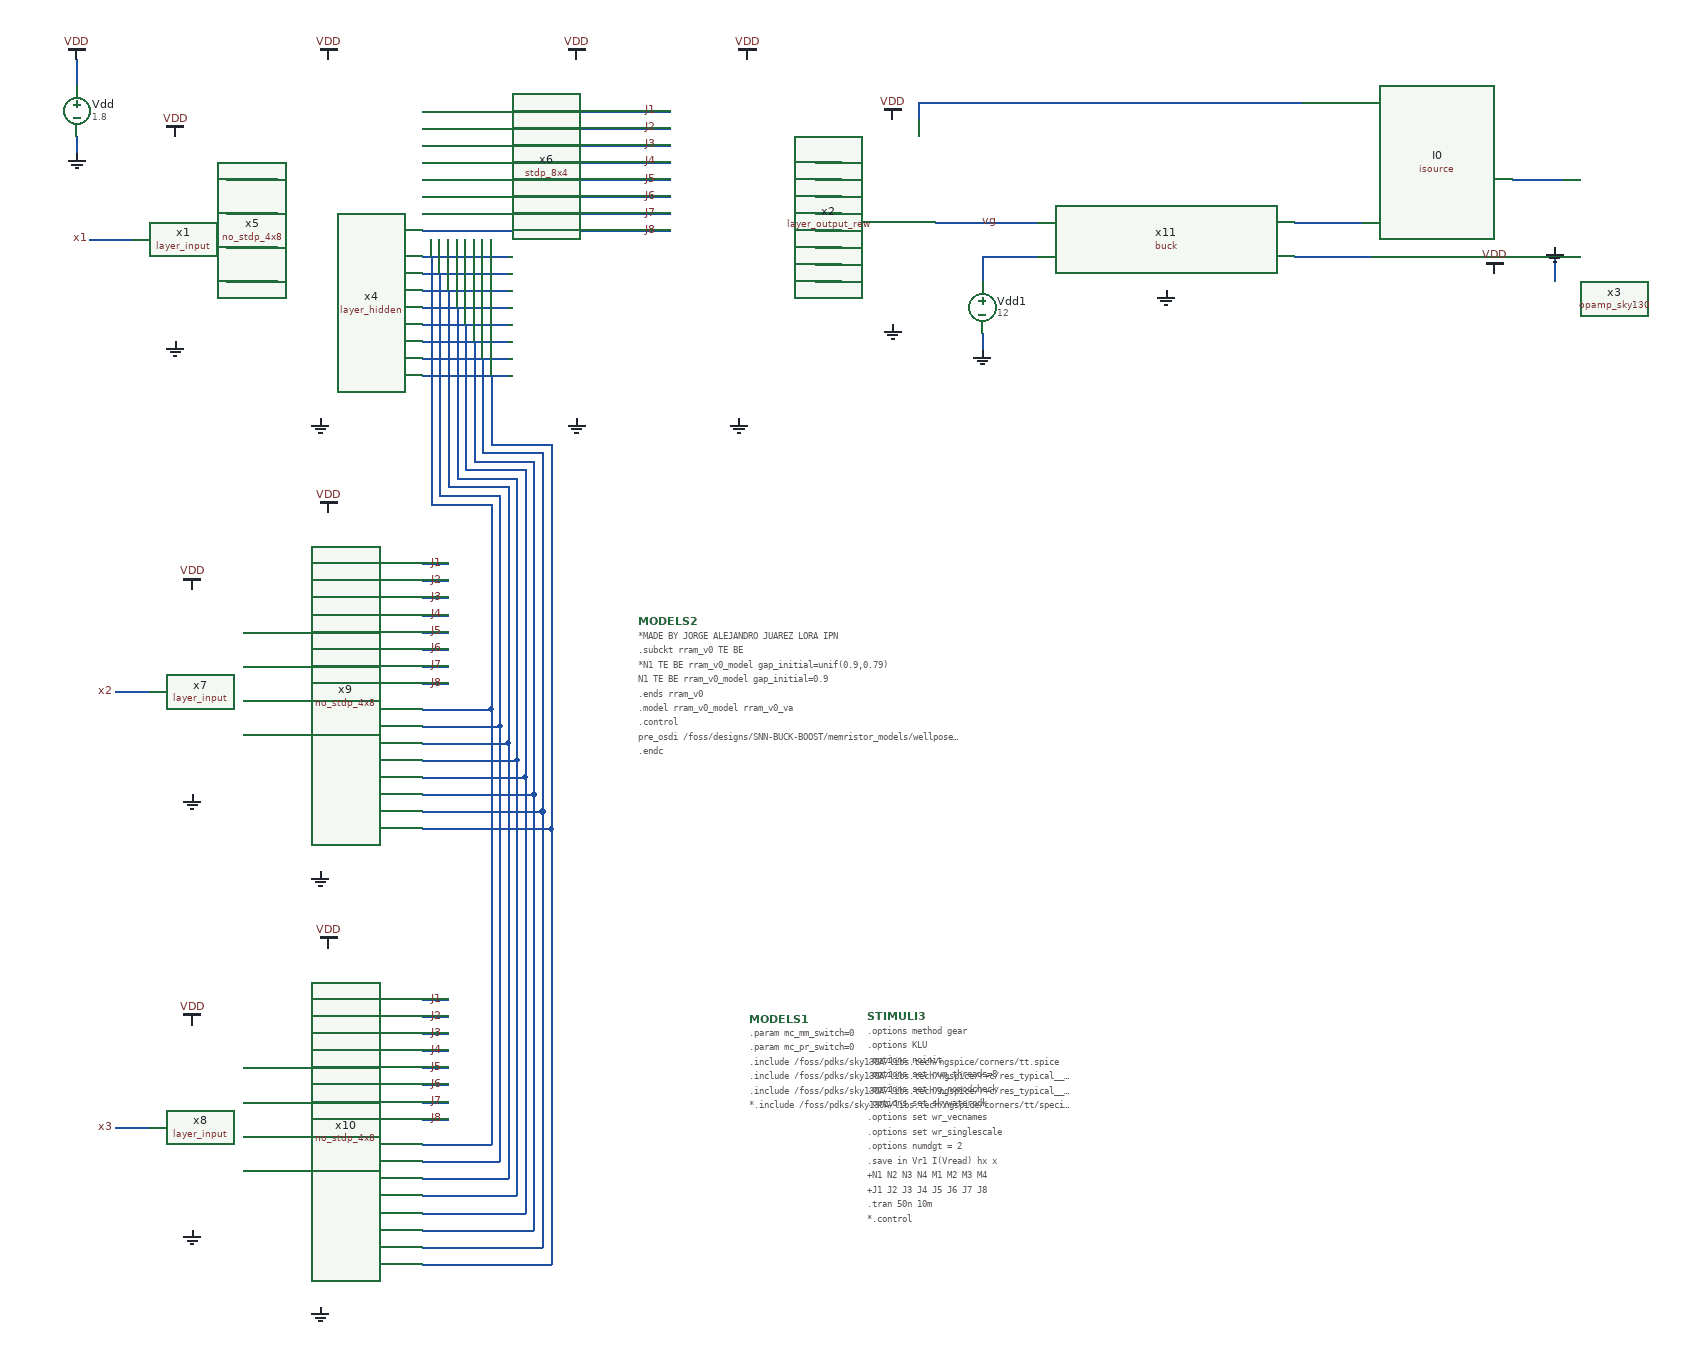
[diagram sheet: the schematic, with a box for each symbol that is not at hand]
v {xschem version=3.4.8RC file_version=1.3}
G {}
K {}
V {}
S {}
F {}
E {}
N 145 -560 145 -530 {
lab=VDD}
N 145 -470 145 -450 {
lab=GND}
N 320 -420 380 -420 {
lab=N1}
N 320 -380 380 -380 {
lab=N2}
N 320 -340 380 -340 {
lab=N3}
N 320 -300 380 -300 {
lab=N4}
N 550 -310 580 -310 {
lab=#net1}
N 550 -330 580 -330 {
lab=#net2}
N 620 -500 840 -500 {
lab=J1}
N 620 -480 840 -480 {
lab=J2}
N 620 -460 840 -460 {
lab=J3}
N 620 -440 840 -440 {
lab=J4}
N 620 -420 840 -420 {
lab=J5}
N 620 -400 840 -400 {
lab=J6}
N 620 -380 840 -380 {
lab=J7}
N 620 -360 840 -360 {
lab=J8}
N 1010 -440 1040 -440 {
lab=M1}
N 1010 -420 1040 -420 {
lab=#net3}
N 1010 -400 1040 -400 {
lab=M2}
N 1010 -380 1040 -380 {
lab=#net4}
N 1010 -360 1040 -360 {
lab=M3}
N 1010 -340 1040 -340 {
lab=#net5}
N 1010 -320 1040 -320 {
lab=M4}
N 1010 -300 1040 -300 {
lab=#net6}
N 1825 -420 1885 -420 {
lab=#net7}
N 1875 -340 1875 -300 {
lab=GND}
N 160 -350 210 -350 {lab=x1}
N 1130 -510 1130 -490 {lab=#net8}
N 1130 -510 1580 -510 {lab=#net8}
N 190 180 230 180 {lab=x2}
N 190 690 230 690 {lab=x3}
N 550 30 580 30 {lab=J1}
N 550 50 580 50 {lab=J2}
N 550 70 580 70 {lab=J3}
N 550 90 580 90 {lab=J4}
N 550 110 580 110 {lab=J5}
N 550 130 580 130 {lab=J6}
N 550 150 580 150 {lab=J7}
N 550 170 580 170 {lab=J8}
N 550 200 630 200 {lab=#net2}
N 630 -40 630 200 {lab=#net2}
N 560 -40 630 -40 {lab=#net2}
N 560 -330 560 -40 {lab=#net2}
N 550 220 640 220 {lab=#net1}
N 640 -50 640 220 {lab=#net1}
N 570 -50 640 -50 {lab=#net1}
N 570 -310 570 -50 {lab=#net1}
N 550 -500 620 -500 {lab=J1}
N 550 -480 620 -480 {lab=J2}
N 550 -460 620 -460 {lab=J3}
N 550 -440 620 -440 {lab=J4}
N 550 -420 620 -420 {lab=J5}
N 550 -400 620 -400 {lab=J6}
N 550 -380 620 -380 {lab=J7}
N 550 -360 620 -360 {lab=J8}
N 580 -330 650 -330 {lab=#net2}
N 580 -310 650 -310 {lab=#net1}
N 550 240 650 240 {lab=#net9}
N 650 -60 650 240 {lab=#net9}
N 580 -60 650 -60 {lab=#net9}
N 550 -290 650 -290 {lab=#net9}
N 550 -270 650 -270 {lab=#net10}
N 550 -250 650 -250 {lab=#net11}
N 550 -230 650 -230 {lab=#net12}
N 550 -210 650 -210 {lab=#net13}
N 550 -190 650 -190 {lab=#net14}
N 580 -290 580 -60 {lab=#net9}
N 550 260 660 260 {lab=#net10}
N 660 -70 660 260 {lab=#net10}
N 590 -70 660 -70 {lab=#net10}
N 590 -270 590 -70 {lab=#net10}
N 550 280 670 280 {lab=#net11}
N 670 -80 670 280 {lab=#net11}
N 600 -80 670 -80 {lab=#net11}
N 600 -250 600 -80 {lab=#net11}
N 550 300 680 300 {lab=#net12}
N 680 -90 680 300 {lab=#net12}
N 610 -90 680 -90 {lab=#net12}
N 610 -230 610 -90 {lab=#net12}
N 550 320 690 320 {lab=#net13}
N 690 -100 690 320 {lab=#net13}
N 620 -100 690 -100 {lab=#net13}
N 620 -210 620 -100 {lab=#net13}
N 550 340 700 340 {lab=#net14}
N 700 -110 700 340 {lab=#net14}
N 630 -110 700 -110 {lab=#net14}
N 630 -190 630 -110 {lab=#net14}
N 550 540 580 540 {lab=J1}
N 550 560 580 560 {lab=J2}
N 550 580 580 580 {lab=J3}
N 550 600 580 600 {lab=J4}
N 550 620 580 620 {lab=J5}
N 550 640 580 640 {lab=J6}
N 550 660 580 660 {lab=J7}
N 550 680 580 680 {lab=J8}
N 630 200 630 710 {lab=#net2}
N 550 710 630 710 {lab=#net2}
N 640 220 640 730 {lab=#net1}
N 550 730 640 730 {lab=#net1}
N 550 750 650 750 {lab=#net9}
N 650 240 650 750 {lab=#net9}
N 660 260 660 770 {lab=#net10}
N 550 770 660 770 {lab=#net10}
N 550 790 670 790 {lab=#net11}
N 670 280 670 790 {lab=#net11}
N 680 300 680 810 {lab=#net12}
N 550 810 680 810 {lab=#net12}
N 550 830 690 830 {lab=#net13}
N 690 320 690 830 {lab=#net13}
N 550 850 700 850 {lab=#net14}
N 700 340 700 850 {lab=#net14}
N 340 110 380 110 {lab=#net15}
N 340 150 380 150 {lab=#net16}
N 340 190 380 190 {lab=#net17}
N 340 230 380 230 {lab=#net18}
N 340 620 380 620 {lab=#net19}
N 340 660 380 660 {lab=#net20}
N 340 700 380 700 {lab=#net21}
N 340 740 380 740 {lab=#net22}
N 1150 -370 1270 -370 {lab=vg}
N 1220 -330 1270 -330 {lab=#net23}
N 1205 -330 1205 -300 {lab=#net23}
N 1205 -330 1220 -330 {lab=#net23}
N 1205 -240 1205 -220 {lab=GND}
N 1570 -330 1660 -330 {lab=#net24}
N 1570 -370 1650 -370 {lab=#net25}
C {devices/vsource.sym} 145 -500 0 0 {name=Vdd value=1.8}
C {devices/gnd.sym} 145 -450 0 0 {name=l5 lab=GND}
C {devices/vdd.sym} 145 -560 0 0 {nname=l4 lab=VDD}
C {devices/code_shown.sym} 802.5 97.5 0 0 {name=MODELS2
only_toplevel=true
format="tcleval( @value )"
value="
*MADE BY JORGE ALEJANDRO JUAREZ LORA IPN

.subckt rram_v0 TE BE
*N1 TE BE rram_v0_model gap_initial=unif(0.9,0.79)
N1 TE BE rram_v0_model gap_initial=0.9
.ends rram_v0

.model rram_v0_model rram_v0_va


.control

pre_osdi /foss/designs/SNN-BUCK-BOOST/memristor_models/wellposed/rram_v0.osdi
.endc

"
spice_ignore=false}
C {layer/layer_input.sym} 230 -250 0 0 {name=x1}
C {devices/gnd.sym} 260 -230 0 0 {name=l8 lab=GND}
C {devices/lab_pin.sym} 350 -420 1 0 {name=p2 sig_type=std_logic lab=N1}
C {devices/lab_pin.sym} 360 -380 1 0 {name=p3 sig_type=std_logic lab=N2}
C {devices/lab_pin.sym} 350 -340 1 0 {name=p4 sig_type=std_logic lab=N3}
C {devices/lab_pin.sym} 350 -300 1 0 {name=p5 sig_type=std_logic lab=N4}
C {devices/lab_pin.sym} 1025 -440 1 0 {name=p6 sig_type=std_logic lab=M1}
C {devices/lab_pin.sym} 1025 -400 1 0 {name=p7 sig_type=std_logic lab=M2}
C {devices/lab_pin.sym} 1025 -360 1 0 {name=p8 sig_type=std_logic lab=M3}
C {devices/lab_pin.sym} 1025 -320 1 0 {name=p9 sig_type=std_logic lab=M4}
C {devices/vdd.sym} 260 -470 0 0 {name=l9 lab=VDD}
C {OPAMP/opamp_sky130.sym} 1815 -360 2 1 {name=x3}
C {devices/lab_pin.sym} 1225 -370 3 1 {name=p10 sig_type=std_logic lab=vg}
C {devices/vdd.sym} 1805 -310 2 0 {name=l19 lab=VDD}
C {devices/isource.sym} 1785 -450 2 1 {name=I0 value=100u}
C {devices/gnd.sym} 1875 -340 2 0 {name=l13 lab=GND}
C {layer/layer_hidden.sym} 480 -360 0 0 {name=x4}
C {Synapse/no_stdp_4x8.sym} 400 -350 0 0 {name=x5}
C {devices/vdd.sym} 440 -560 0 0 {name=l3 lab=VDD}
C {devices/vdd.sym} 730 -560 0 0 {name=l4 lab=VDD}
C {devices/gnd.sym} 430 -140 0 0 {name=l6 lab=GND}
C {devices/gnd.sym} 730 -140 0 0 {name=l7 lab=GND}
C {Synapse/stdp_8x4.sym} 620 -380 0 0 {name=x6}
C {devices/gnd.sym} 1100 -250 0 0 {name=l11 lab=GND}
C {devices/gnd.sym} 920 -140 0 0 {name=l12 lab=GND}
C {devices/vdd.sym} 930 -560 0 0 {name=l14 lab=VDD}
C {devices/vdd.sym} 1100 -490 0 0 {name=l15 lab=VDD}
C {devices/lab_pin.sym} 825 -500 1 0 {name=p13 sig_type=std_logic lab=J1}
C {devices/lab_pin.sym} 825 -480 1 0 {name=p14 sig_type=std_logic lab=J2}
C {devices/lab_pin.sym} 825 -460 1 0 {name=p15 sig_type=std_logic lab=J3}
C {devices/lab_pin.sym} 825 -440 1 0 {name=p16 sig_type=std_logic lab=J4}
C {devices/lab_pin.sym} 825 -420 1 0 {name=p17 sig_type=std_logic lab=J5}
C {devices/lab_pin.sym} 825 -400 1 0 {name=p18 sig_type=std_logic lab=J6}
C {devices/lab_pin.sym} 825 -380 1 0 {name=p19 sig_type=std_logic lab=J7}
C {devices/lab_pin.sym} 825 -360 1 0 {name=p20 sig_type=std_logic lab=J8}
C {devices/code.sym} 932.5 562.5 0 0 {name=MODELS1
only_toplevel=true
format="tcleval( @value )"
value="

.param mc_mm_switch=0
.param mc_pr_switch=0
.include /foss/pdks/sky130A/libs.tech/ngspice/corners/tt.spice
.include /foss/pdks/sky130A/libs.tech/ngspice/r+c/res_typical__cap_typical.spice
.include /foss/pdks/sky130A/libs.tech/ngspice/r+c/res_typical__cap_typical__lin.spice
*.include /foss/pdks/sky130A/libs.tech/ngspice/corners/tt/specialized_cells.spice

"
spice_ignore=false}
C {devices/code.sym} 1070 560 0 0 {name=STIMULI3 
only_toplevel=true
place=end
value="

.options method gear
.options KLU
.options noinit
.options set num_threads=8
.options set ng_nomodcheck
.options set skywaterpdk
.options set wr_vecnames
.options set wr_singlescale
.options numdgt = 2
.save in Vr1 I(Vread) hx x
+N1 N2 N3 N4 M1 M2 M3 M4
+J1 J2 J3 J4 J5 J6 J7 J8 

.tran 50n 10m
*.control
*	run
*	write /home/alex/Desktop/EDA/SNN_IPN/sim_results/data.raw
*.endc
"
spice_ignore = false}
C {devices/lab_pin.sym} 160 -350 0 0 {name=p21 sig_type=std_logic lab=x1
}
C {/foss/designs/SNN_IPN/layer/layer_output_rew.sym} 1060 -270 0 0 {name=x2}
C {layer/layer_input.sym} 250 280 0 0 {name=x7}
C {devices/gnd.sym} 280 300 0 0 {name=l10 lab=GND}
C {devices/vdd.sym} 280 60 0 0 {name=l16 lab=VDD}
C {devices/lab_pin.sym} 190 180 0 0 {name=p12 sig_type=std_logic lab=x2
}
C {layer/layer_input.sym} 250 790 0 0 {name=x8}
C {devices/gnd.sym} 280 810 0 0 {name=l17 lab=GND}
C {devices/vdd.sym} 280 570 0 0 {name=l18 lab=VDD}
C {devices/lab_pin.sym} 190 690 0 0 {name=p22 sig_type=std_logic lab=x3
}
C {Synapse/no_stdp_4x8.sym} 400 180 0 0 {name=x9}
C {devices/vdd.sym} 440 -30 0 0 {name=l20 lab=VDD}
C {devices/gnd.sym} 430 390 0 0 {name=l21 lab=GND}
C {Synapse/no_stdp_4x8.sym} 400 690 0 0 {name=x10}
C {devices/vdd.sym} 440 480 0 0 {name=l22 lab=VDD}
C {devices/gnd.sym} 430 900 0 0 {name=l23 lab=GND}
C {devices/lab_pin.sym} 575 30 1 0 {name=p23 sig_type=std_logic lab=J1}
C {devices/lab_pin.sym} 575 50 1 0 {name=p24 sig_type=std_logic lab=J2}
C {devices/lab_pin.sym} 575 70 1 0 {name=p25 sig_type=std_logic lab=J3}
C {devices/lab_pin.sym} 575 90 1 0 {name=p26 sig_type=std_logic lab=J4}
C {devices/lab_pin.sym} 575 110 1 0 {name=p27 sig_type=std_logic lab=J5}
C {devices/lab_pin.sym} 575 130 1 0 {name=p28 sig_type=std_logic lab=J6}
C {devices/lab_pin.sym} 575 150 1 0 {name=p29 sig_type=std_logic lab=J7}
C {devices/lab_pin.sym} 575 170 1 0 {name=p30 sig_type=std_logic lab=J8}
C {devices/lab_pin.sym} 575 540 1 0 {name=p31 sig_type=std_logic lab=J1}
C {devices/lab_pin.sym} 575 560 1 0 {name=p32 sig_type=std_logic lab=J2}
C {devices/lab_pin.sym} 575 580 1 0 {name=p33 sig_type=std_logic lab=J3}
C {devices/lab_pin.sym} 575 600 1 0 {name=p34 sig_type=std_logic lab=J4}
C {devices/lab_pin.sym} 575 620 1 0 {name=p35 sig_type=std_logic lab=J5}
C {devices/lab_pin.sym} 575 640 1 0 {name=p36 sig_type=std_logic lab=J6}
C {devices/lab_pin.sym} 575 660 1 0 {name=p37 sig_type=std_logic lab=J7}
C {devices/lab_pin.sym} 575 680 1 0 {name=p38 sig_type=std_logic lab=J8}
C {/foss/designs/SNN-BUCK-BOOST/DC_DC/buck.sym} 1420 -350 0 0 {name=x11}
C {devices/vsource.sym} 1205 -270 0 0 {name=Vdd1 value=12}
C {devices/gnd.sym} 1205 -220 0 0 {name=l1 lab=GND}
C {devices/gnd.sym} 1420 -290 0 0 {name=l2 lab=GND}
